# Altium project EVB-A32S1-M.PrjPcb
1 sheet, 0 parts. Net scope: global (net labels, ports and power ports of the same name join across sheets).

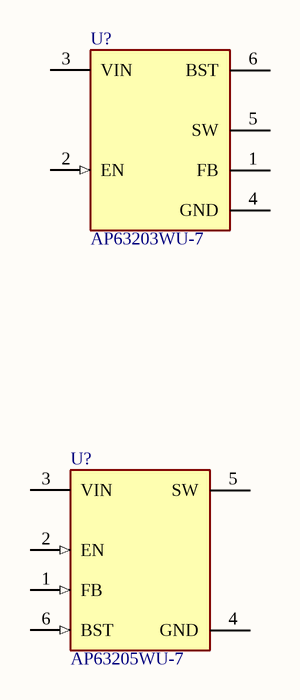
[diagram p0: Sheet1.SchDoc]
## Sheet Sheet1.SchDoc
size A4; SheetNumber: 1; SheetTotal: 1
